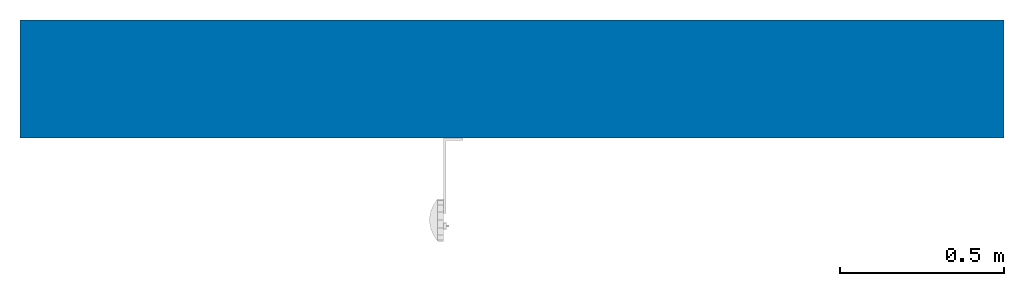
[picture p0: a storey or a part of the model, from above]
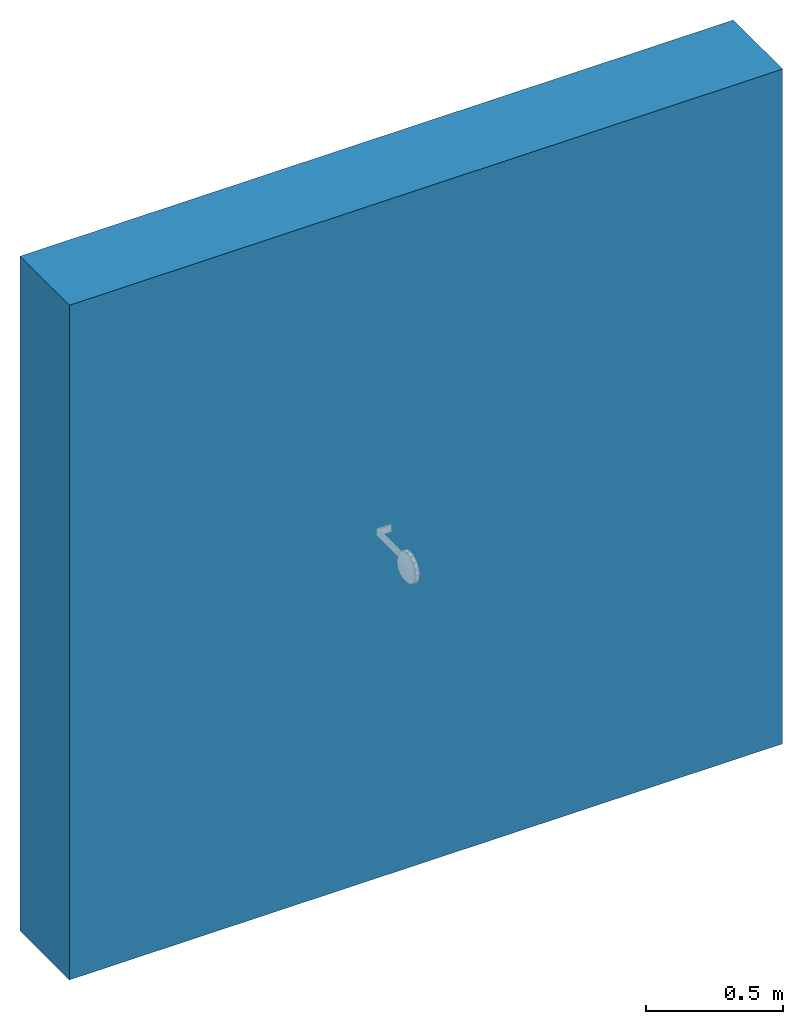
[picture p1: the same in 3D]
Properties of the parts of a building model (IFC2X3)

# File
Description: ViewDefinition [CoordinationView_V2.0]
File name: Projektnummer
Time: 2019-08-29T13:19:18
Written by: The EXPRESS Data Manager Version 5.02.0100.07 : 28 Aug 2013
Made in: 20160225_1515(x64) - Exporter 17.0.416.0 - Alternate UI 17.12.14.0
Comment: STEP Physical File produced by: The EXPRESS Data Manager Version 5.02.0100.07 : 28 Aug 2013 * Module: EDMstepFileFactory/EDMstandAlone * Creation date: Thu Aug 29 13:19:18 2019 * Host: B-BIM-NB-4736 * Database: C:\Users\Enkler\AppData\Local\Temp\{894446A9-EEB4-4482-A51A-52796269ADFB}\ifc * Database version: 5507 * Database creation date: Thu Aug 29 13:19:17 2019 * Schema: IFC2X3 * Model: DataRepository.ifc * Model creation date: Thu Aug 29 13:19:17 2019 * Header model: DataRepository.ifc_HeaderModel * Header model creation date: Thu Aug 29 13:19:17 2019 * EDMuser: sdai-user * EDMgroup: sdai-group * License ID and type: 5605 : Permanent license. Expiry date: * EDMstepFileFactory options: 020000

# IfcProject, Projektnummer
LongName: Projektname; Phase: Projektstatus

# IfcSite, Default
RefLatitude: 52, 30, 59, 765625; RefLongitude: 13, 23, 59, 998626; RefElevation: 0 m
Sonstige - Kategorie: Projektinformationen; Kundenname: Bauherr; Projektadresse: Projektadresse; Projektausgabedatum: Projekt Datum; Projektname: Projektname; Projektnummer: Projektnummer; Projektstatus: Projektstatus; Verfasser eMail: E-Mail; Verfasser Firma 1: Firma 1; Verfasser Firma 2: Firma 2; Verfasser PLZ Ort: PLZ Ort; Verfasser Strasse: Strasse; Verfasser Telefax: Telefax; Verfasser Telefon: Telefon

# IfcBuilding
Pset_BuildingCommon - NumberOfStoreys: 1
Sonstige - Kategorie: Projektinformationen; Kundenname: Bauherr; Projektadresse: Projektadresse; Projektausgabedatum: Projekt Datum; Projektname: Projektname; Projektnummer: Projektnummer; Projektstatus: Projektstatus; Verfasser eMail: E-Mail; Verfasser Firma 1: Firma 1; Verfasser Firma 2: Firma 2; Verfasser PLZ Ort: PLZ Ort; Verfasser Strasse: Strasse; Verfasser Telefax: Telefax; Verfasser Telefon: Telefon

# IfcBuildingStorey, Ebene 0
LongName: Ebene 0; Elevation: 0 m
Sonstige - Kategorie: Ebenen; Familienname: Ebene; Familie: Ebene: Ebene; Familie und Typ: Ebene: Ebene; Typ: Ebene: Ebene; Typ-ID: Ebene: Ebene
ID-Daten - Typname: Ebene; Tragwerk: no; Gebäudegeschoss: yes; Name: Ebene 0
Grafiken - Farbe: 16711680; Linienmuster: Verdeckt; Linienstärke: 1; Symbol: Beschriftung Ebene: Beschriftung Ebene; Symbol bei Ende 1 Standard: no; Symbol bei Ende 2 Standard: yes
Abhängigkeiten - Basishöhe: Projekt-Basispunkt; Ansicht: 0 m
Abmessungen - Höhe für Berechnung: 0 m

# IfcBuildingElementProxy: GIRA_207400_ENG, GIRA_207400_ENG:GIRA_207400_ENG:389509
In: Ebene 0
Type - Material: White
Type - Abhängigkeiten - Vorgabe-Ansicht: 1.2192 m
Type - Allgemein - Bus connection included YesNo: no; Bus system KNX radio YesNo: no; Bus system KNX YesNo: yes; Bus system LON YesNo: no; Bus system Powernet YesNo: no; Bus system radio frequent YesNo: no; Colour: Other; Degree of protection (IP) Text: IP21; HeinzeBIM: https://www.heinze.de/bim/weather-st-plus-knx/c85c4f16caf95ba884865c4d56ed2c45a52e3287; Model Text: Other; Mounting method Text: DRA (DIN-rail adapter); Radio frequent bidirectional YesNo: no
Type - ID-Daten - Beschreibung: Weather st.Plus KNX,KNX weather station Plus,,,Features:,- The KNX weather station records the wind speed, wind direction, precipitation, global radiation, temperature, twilight, relative humidity, air pressure and with four sensors the brightness in different directions.,- The maximum value of the brightness sensors, absolute humidity, perceived temperature and comfort are calculated using the measured data.,- An area of application is the automatic, weather-dependent shading system specifically for home use.,- The weather station monitors some of its own major functions and reports corresponding faults automatically via message objects on the bus.,- Monitoring of the applied voltage. The failure is reported via a communications object on the bus.,- With integrated bus coupler.,- Mounting outdoors on a pole or on the wall.,- The position of the installation site can be determined via GPS.,Functions:,- Two limits with an adjustable hysteresis per sensor can be parameterised internally or specified as 8-bit or 16-bit values.,- The teach-in function enables the application of a current measured value to a limit.,- All limit objects have a parameterisable switch-on and switch-off delay.,- 16 logic gates (AND, AND with return, OR, Exclusive OR, NAND, NOR) with up to four inputs for external and internal 1-bit values.,- 4 blocking elements for blocking functions or manual operation.,- Automatic shading control of up to 8 facades can be implemented with sun position-dependent tracking of the slats and hanging height control.,- All values can be output when values change and cyclically. The outputs of the blocking elements can be sent only if the value changes.,- Weather stations can be cascaded via the logic functions. This is recommended for expansion of functions (measuring the wind strength on different facades) or for significantly increased functional reliability through redundance.,,Notes :,- Measured values apply for the installation site. Deviations from other weather services are possible.,- All accuracy specifications of the measured values refer to the respective measurement range send value.; GTIN: 4010337031185; HAN: 207400; Hersteller: Gira; Typname: Weather st. Plus KNX; URL: https://www.gira.de/
Type - Sonstige - Kategorie: Elektroinstallationen; Familienname: GIRA_207400_ENG
Pset_BuildingElementProxyCommon - Reference: GIRA_207400_ENG
Pset_ManufacturerTypeInformation - Manufacturer: Gira
Abhängigkeiten - Basisbauteil: Basiswand : MW 24.0 WD 12.0; Ebene: Ebene: Ebene 0; Erhebung: 1.54025 m
Abmessungen - Fläche: 0.0862442 m2; Volumen: 0.00416952 m3
ID-Daten - Kennzeichen: 1
Phasen - Phase erstellt: Phase 1
Sonstige - Bauteillistenebene: Ebene: Ebene 0; Familie: GIRA_207400_ENG: GIRA_207400_ENG; Familie und Typ: GIRA_207400_ENG: GIRA_207400_ENG; Typ: GIRA_207400_ENG: GIRA_207400_ENG; Typ-ID: GIRA_207400_ENG: GIRA_207400_ENG

# IfcWallStandardCase: Basiswand:MW 24.0 WD 12.0, Basiswand:MW 24.0 WD 12.0:388662
In: Ebene 0
Type - PredefinedType: STANDARD; Material: Wärmedämmung - hart 0.12 m, Mauerwerk - Ziegel, verputzt 0.24 m
Type - Analytische Eigenschaften - Absorptionsgrad: 0.7; Rauigkeit: 3; Thermischer Widerstand (R): 3.87302; Thermisch wirksame Masse: 316537; Wärmeübergangskoeffizient (U): 0.258197
Type - Grafiken - Farbfüllung für groben Maßstab: 0; Füllmuster für groben Maßstab: Standard - Füllung
Type - ID-Daten - Beschreibung: Mauerwerk 24.0 cm, Wärmedämmung 12.0 cm; Typenkommentare: Mehrschaliges Mauerwerk; Typname: MW 24.0 WD 12.0
Type - Konstruktion - Abschluss an Öffnungen: Keine; Abschluss an Wänden: Keine; Breite: 0.36 m; Funktion: Außen
Type - Materialien und Oberflächen - Tragendes Material: Mauerwerk - Ziegel, verputzt
Type - Sonstige - Kategorie: Wände; Familienname: Basiswand
Abhängigkeiten - Abhängigkeit oben: Ebene: Ebene 1; Abhängigkeit unten: Ebene: Ebene 0; Basislinie: Wandachse; Für Körper: no; Nicht verknüpfte Höhe: 3 m; Oberkante ist fixiert.: no; Raumbegrenzung: yes; Unterkante ist fixiert: no; Verlängerungsabstand oben: 0 m; Verlängerungsabstand unten: 0 m; Versatz oben: 0 m; Versatz unten: 0 m
Abmessungen - Fläche: 9 m2; Länge: 3 m; Volumen: 3.24 m3
Phasen - Phase erstellt: Phase 1
Sonstige - Familie: Basiswand: MW 24.0 WD 12.0; Familie und Typ: Basiswand: MW 24.0 WD 12.0; Typ: Basiswand: MW 24.0 WD 12.0; Typ-ID: Basiswand: MW 24.0 WD 12.0
Tragwerk - Berechnungsmodell aktivieren: no; Tragwerk: no; Tragwerksverwendung: Nichttragend
Pset_WallCommon - Reference: MW 24.0 WD 12.0; LoadBearing: no; ExtendToStructure: no; IsExternal: yes; ThermalTransmittance: 0.258197 kg/K/s3
